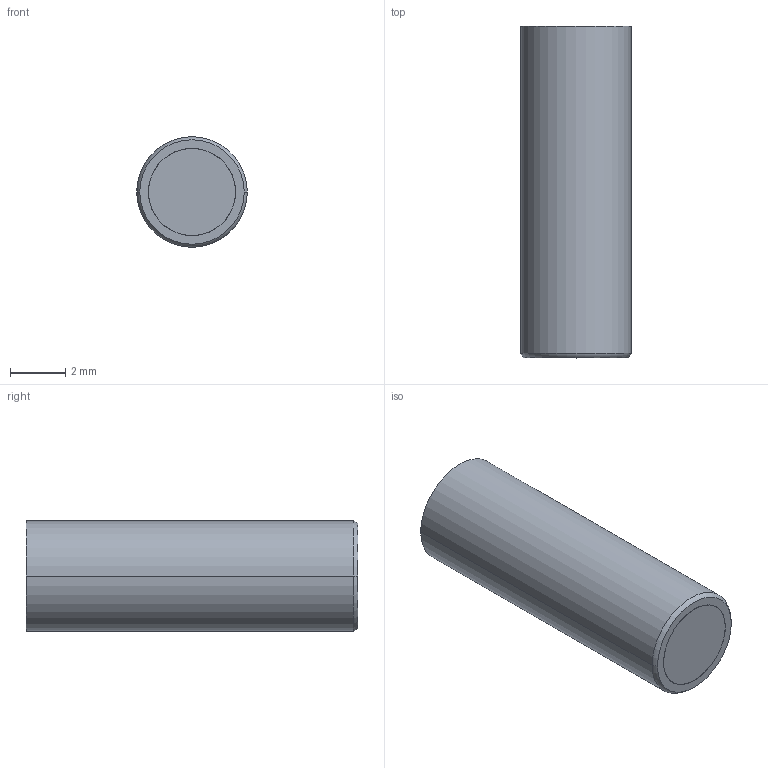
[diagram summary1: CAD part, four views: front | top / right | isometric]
STEP (ISO 10303-21) file: header records copied from the file, then geometry measured from it (millimetres).
FILE_DESCRIPTION (( 'STEP AP214' ), '1' );
FILE_NAME ('FA 042212-21.STEP', '2020-08-10T10:54:30', ( '' ), ( '' ), 'SwSTEP 2.0', 'SolidWorks 2019', '' );
FILE_SCHEMA (( 'AUTOMOTIVE_DESIGN' ));
Length unit declared in the file: millimetre
Products named in the file (6): FA 042200-2; 9FA 042212; FA 042200-3; IA 227514; FA 042200-1; FA 042212-21
Assembly tree (5 placements, depth 2):
  FA 042212-21
    9FA 042212
    IA 227514
    FA 042200-3
    FA 042200-2
    FA 042200-1
Bounding box: 4 x 12 x 4 mm (x, y, z)
Volume: 123 mm3; surface area: 464.1 mm2
Topology: 5 solids, 5 shells, 300 faces, 753 edges, 495 vertices
Faces by surface type: cylinder 137, plane 134, cone 14, bspline 13, torus 2
Entity records: 10881 total; most frequent: CARTESIAN_POINT 3158, DIRECTION 1609, ORIENTED_EDGE 1502, EDGE_CURVE 751, AXIS2_PLACEMENT_3D 588, VERTEX_POINT 495, VECTOR 433, LINE 433
One B-rep face of a CAD part: STEP entity #10817.
In plain terms, the planar face has unit normal (-1, 0, 0).
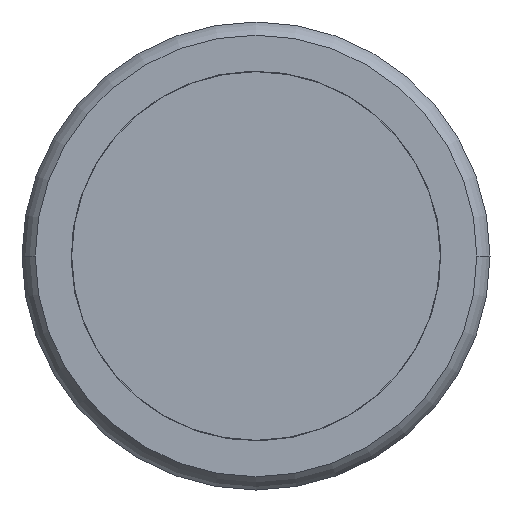
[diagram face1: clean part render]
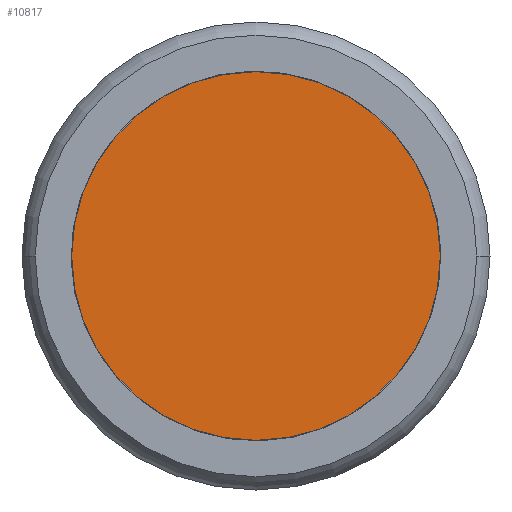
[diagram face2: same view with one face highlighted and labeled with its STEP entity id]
Its self-contained STEP definition (entity closure, numbers rounded to 3 decimals):
#503 = DIRECTION ( 'NONE',  ( 0., 1., 0. ) ) ;
#2057 = AXIS2_PLACEMENT_3D ( 'NONE', #8671, #3648, #3758 ) ;
#2295 = CARTESIAN_POINT ( 'NONE',  ( 0.374, 0., 0. ) ) ;
#2372 = CARTESIAN_POINT ( 'NONE',  ( 0.374, 0., 0. ) ) ;
#2403 = CARTESIAN_POINT ( 'NONE',  ( 0.374, 0., 1.58 ) ) ;
#2429 = AXIS2_PLACEMENT_3D ( 'NONE', #2372, #7459, #503 ) ;
#3240 = DIRECTION ( 'NONE',  ( 0., 1., 0. ) ) ;
#3648 = DIRECTION ( 'NONE',  ( 1., 0., 0. ) ) ;
#3723 = VERTEX_POINT ( 'NONE', #6431 ) ;
#3758 = DIRECTION ( 'NONE',  ( 0., 1., 0. ) ) ;
#4766 = ORIENTED_EDGE ( 'NONE', *, *, #10925, .F. ) ;
#5439 = CIRCLE ( 'NONE', #10752, 1.58 ) ;
#5479 = PLANE ( 'NONE',  #2057 ) ;
#6431 = CARTESIAN_POINT ( 'NONE',  ( 0.374, 0., -1.58 ) ) ;
#6652 = EDGE_CURVE ( 'NONE', #3723, #6986, #7255, .T. ) ;
#6986 = VERTEX_POINT ( 'NONE', #2403 ) ;
#7064 = FACE_OUTER_BOUND ( 'NONE', #9711, .T. ) ;
#7255 = CIRCLE ( 'NONE', #2429, 1.58 ) ;
#7459 = DIRECTION ( 'NONE',  ( 1., 0., 0. ) ) ;
#8671 = CARTESIAN_POINT ( 'NONE',  ( 0.374, 1.735, -10. ) ) ;
#9040 = DIRECTION ( 'NONE',  ( 1., 0., 0. ) ) ;
#9711 = EDGE_LOOP ( 'NONE', ( #4766, #10779 ) ) ;
#10752 = AXIS2_PLACEMENT_3D ( 'NONE', #2295, #9040, #3240 ) ;
#10779 = ORIENTED_EDGE ( 'NONE', *, *, #6652, .F. ) ;
#10817 = ADVANCED_FACE ( 'NONE', ( #7064 ), #5479, .F. ) ;
#10925 = EDGE_CURVE ( 'NONE', #6986, #3723, #5439, .T. ) ;
